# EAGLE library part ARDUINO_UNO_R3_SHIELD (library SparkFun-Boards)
Arduino R3 Shield Footprint Shield form compatible with the Arduino Uno R3. SparkFun Products: MG2639 Cellular Shield MIDI Shield R3 Stackable Headers Kit

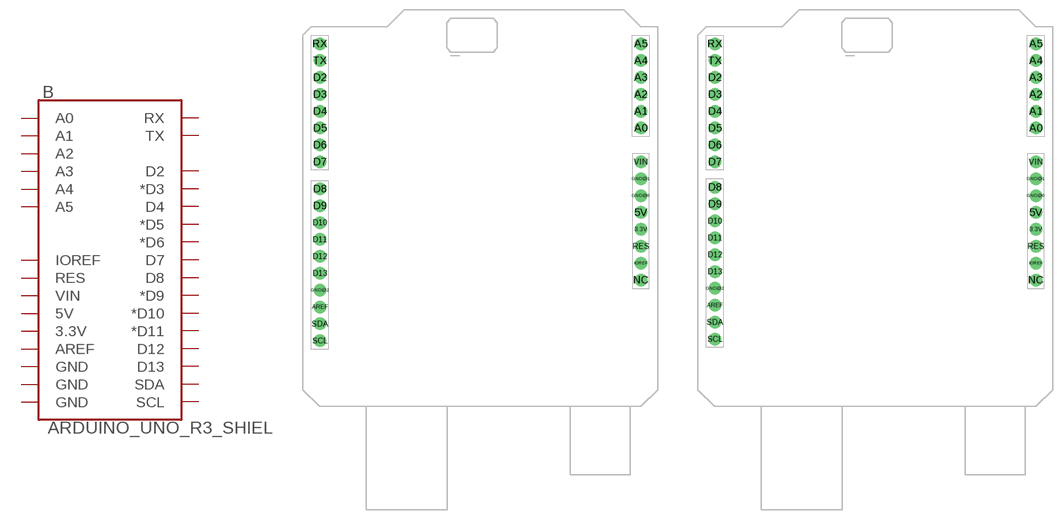
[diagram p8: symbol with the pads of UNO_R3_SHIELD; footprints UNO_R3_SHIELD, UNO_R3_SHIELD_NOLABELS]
Designator prefix B

## ARDUINO_UNO_R3_SHIELDBASIC  [UNO_R3_SHIELD]
3.3V  3.3V
5V  5V
A0  A0
A1  A1
A2  A2
A3  A3
A4  A4
A5  A5
AREF  AREF
D2  D2
D3  *D3
D4  D4
D5  *D5
D6  *D6
D7  D7
D8  D8
D9  *D9
D10  *D10
D11  *D11
D12  D12
D13  D13
GND@0  GND
GND@1  GND
GND@2  GND
IOREF  IOREF
RES  RES
RX  RX
SCL  SCL
SDA  SDA
TX  TX
VIN  VIN

## ARDUINO_UNO_R3_SHIELDNOLABELS  [UNO_R3_SHIELD_NOLABELS]
Pads as for UNO_R3_SHIELD

## ARDUINO_UNO_R3_SHIELDUNO_R3_SHIELD_LOCK  [UNO_R3_SHIELD_LOCK]
Pads as for UNO_R3_SHIELD

## ARDUINO_UNO_R3_SHIELDUNO_R3_SHIELD_NOLABELS_LOCK  [UNO_R3_SHIELD_NOLABELS_LOCK]
Pads as for UNO_R3_SHIELD

## Footprint UNO_R3_SHIELD (pad centres in mm)
Arduino Uno-Compatible Footprint No holes, no ICSP connections. Specifications: Pin count: 32 Pin pitch: 0.1" Area:2.1x2.35" Example device(s): Arduino Uno R3 Shield
drill 1.016 pad 1.88: 3.3V 24.13,-2.54; 5V 24.13,0; A0 24.13,12.7; A1 24.13,15.24; A2 24.13,17.78; A3 24.13,20.32; A4 24.13,22.86; A5 24.13,25.4; AREF -24.13,-14.224; D2 -24.13,20.32; D3 -24.13,17.78; D4 -24.13,15.24; D5 -24.13,12.7; D6 -24.13,10.16; D7 -24.13,7.62; D8 -24.13,3.556; D9 -24.13,1.016; D10 -24.13,-1.524; D11 -24.13,-4.064; D12 -24.13,-6.604; D13 -24.13,-9.144; GND@0 24.13,2.54; GND@1 24.13,5.08; GND@2 -24.13,-11.684; IOREF 24.13,-7.62; NC 24.13,-10.16; RES 24.13,-5.08; RX -24.13,25.4; SCL -24.13,-19.304; SDA -24.13,-16.764; TX -24.13,22.86; VIN 24.13,7.62

## Footprint UNO_R3_SHIELD_NOLABELS (pad centres in mm)
Arduino Uno-Compatible Footprint No holes, no ICSP connections, no silk labels. Specifications: Pin count: 32 Pin pitch: 0.1" Area:2.1x2.35" Example device(s): Arduino Uno R3 Shield
drill 1.016 pad 1.88: 3.3V 24.13,-3.81; 5V 24.13,-1.27; A0 24.13,11.43; A1 24.13,13.97; A2 24.13,16.51; A3 24.13,19.05; A4 24.13,21.59; A5 24.13,24.13; AREF -24.13,-15.24; D2 -24.13,19.05; D3 -24.13,16.51; D4 -24.13,13.97; D5 -24.13,11.43; D6 -24.13,8.89; D7 -24.13,6.35; D8 -24.13,2.54; D9 -24.13,0; D10 -24.13,-2.54; D11 -24.13,-5.08; D12 -24.13,-7.62; D13 -24.13,-10.16; GND@0 24.13,1.27; GND@1 24.13,3.81; GND@2 -24.13,-12.7; IOREF 24.13,-8.89; NC 24.13,-11.43; RES 24.13,-6.35; RX -24.13,24.13; SCL -24.13,-20.32; SDA -24.13,-17.78; TX -24.13,21.59; VIN 24.13,6.35

## Footprint UNO_R3_SHIELD_LOCK (pad centres in mm)
Arduino Uno-Compatible Footprint No holes, no ICSP connections. Locking footprint for headers. Specifications: Pin count: 32 Pin pitch: 0.1" Area:2.1x2.35" Example device(s): Arduino Uno R3 Shield
drill 1.016 pad 1.88: 3.3V 24.13,-3.81; 5V 24.384,-1.27; A0 24.384,11.43; A1 24.13,13.97; A2 24.384,16.51; A3 24.13,19.05; A4 24.384,21.59; A5 24.13,24.13; AREF -24.384,-15.494; D2 -24.13,19.05; D3 -24.384,16.51; D4 -24.13,13.97; D5 -24.384,11.43; D6 -24.13,8.89; D7 -24.384,6.35; D8 -24.13,2.286; D9 -24.384,-0.254; D10 -24.13,-2.794; D11 -24.384,-5.334; D12 -24.13,-7.874; D13 -24.384,-10.414; GND@0 24.13,1.27; GND@1 24.384,3.81; GND@2 -24.13,-12.954; IOREF 24.13,-8.89; NC 24.384,-11.43; RES 24.384,-6.35; RX -24.13,24.13; SCL -24.13,-20.574; SDA -24.13,-18.034; TX -24.384,21.59; VIN 24.13,6.35

## Footprint UNO_R3_SHIELD_NOLABELS_LOCK (pad centres in mm)
Arduino Uno-Compatible Footprint No holes, no ICSP connections, no silk labels. Looking footprint for headers. Specifications: Pin count: 32 Pin pitch: 0.1" Area:2.1x2.35" Example device(s): Arduino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
drill 1.016 pad 1.88: 3.3V 24.13,-3.81; 5V 24.384,-1.27; A0 24.384,11.43; A1 24.13,13.97; A2 24.384,16.51; A3 24.13,19.05; A4 24.384,21.59; A5 24.13,24.13; AREF -24.384,-15.494; D2 -24.13,19.05; D3 -24.384,16.51; D4 -24.13,13.97; D5 -24.384,11.43; D6 -24.13,8.89; D7 -24.384,6.35; D8 -24.13,2.286; D9 -24.384,-0.254; D10 -24.13,-2.794; D11 -24.384,-5.334; D12 -24.13,-7.874; D13 -24.384,-10.414; GND@0 24.13,1.27; GND@1 24.384,3.81; GND@2 -24.13,-12.954; IOREF 24.13,-8.89; NC 24.384,-11.43; RES 24.384,-6.35; RX -24.13,24.13; SCL -24.13,-20.574; SDA -24.13,-18.034; TX -24.384,21.59; VIN 24.13,6.35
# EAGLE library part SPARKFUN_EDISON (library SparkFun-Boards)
SparkFun Edison The Intel® Edison is an ultra small computing platform that will change the way you look at embedded electronics. Each Edison packs a huge amount of tech goodies into a tiny package while still providing the same robust strength of your go-to single board computer. Powered by the Intel® Atom™ SoC dual-core CPU and including an integrated WiFi, Bluetooth LE, and a 70-pin connector to attach a veritable slew of shield-like “Blocks” which can be stacked on top of each other. This device includes footprints for the Edison module itself, as well as the basic board outline used for our Edison blocks. SparkFun Products: Intel Edison SparkFun Console Block SparkFun GPIO Block SparkFun Battery Block SparkFun Base Block SparkFun 9DOF Block SparkFun OLED Block SparkFun Dual H-Bridge Block SparkFun microSD Block SparkFun ADC Block SparkFun I2C Block SparkFun Arduino Block SparkFun Power Block SparkFun PWM Block SparkFun Raspberry Pi Block SparkFun UART Block

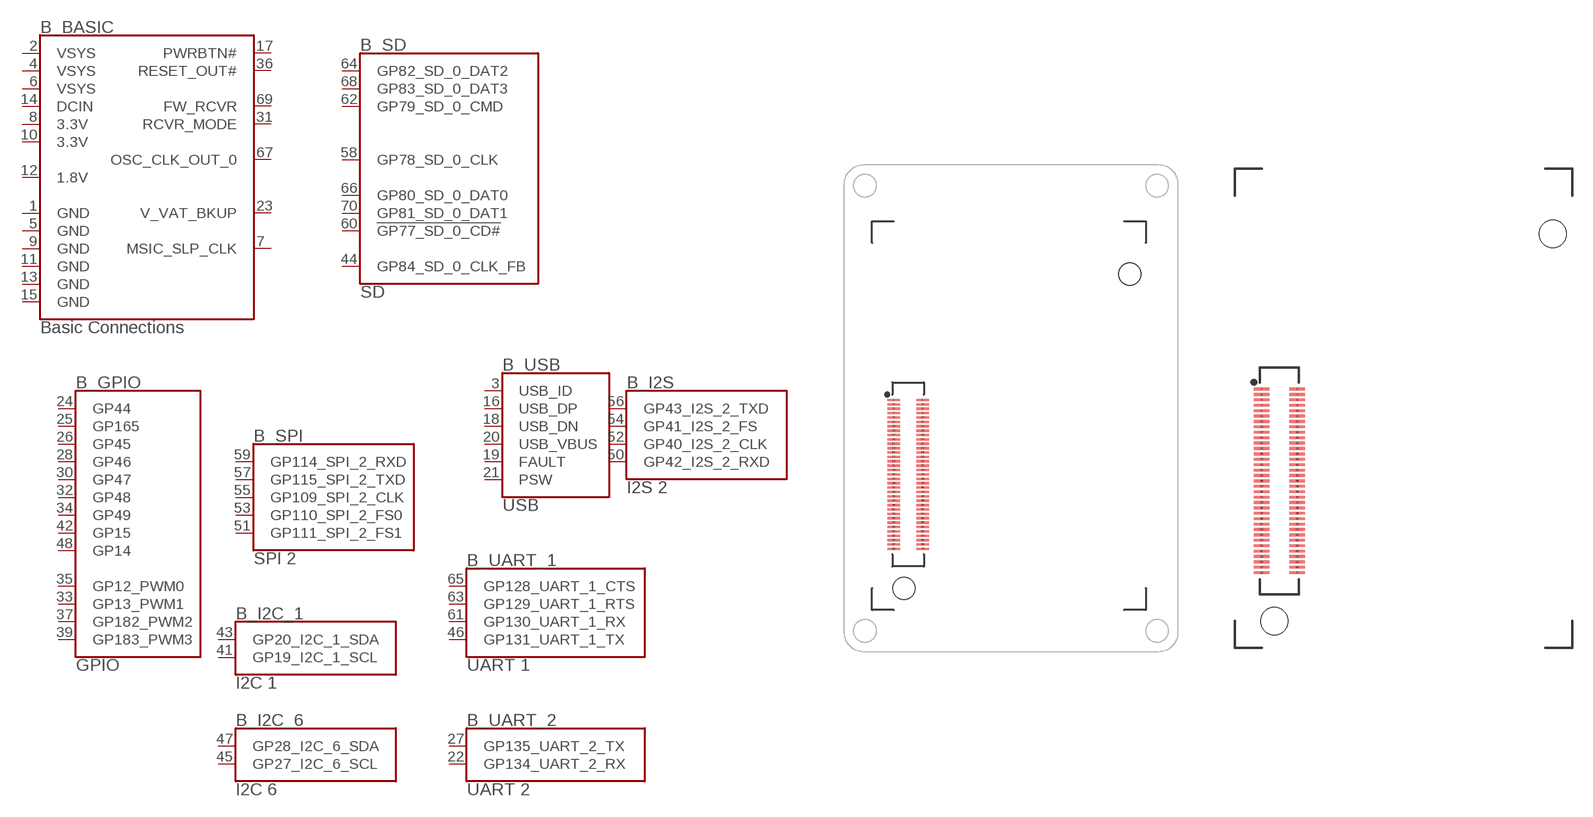
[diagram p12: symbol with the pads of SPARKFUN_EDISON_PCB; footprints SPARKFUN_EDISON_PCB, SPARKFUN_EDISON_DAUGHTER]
Designator prefix B; gates _BASIC=EDISON_CONNECTOR_BASE _GPIO=EDISON_CONNECTOR_GPIO _I2C_1=EDISON_CONNECTOR_I2C_1 _I2C_6=EDISON_CONNECTOR_I2C_6 _I2S=EDISON_CONNECTOR_I2S_2 _SD=EDISON_CONNECTOR_SD _SPI=EDISON_CONNECTOR_SPI_2 _UART_1=EDISON_CONNECTOR_UART_1 _UART_2=EDISON_CONNECTOR_UART_2 _USB=EDISON_CONNECTOR_USB

## SPARKFUN_EDISONPCB  [SPARKFUN_EDISON_PCB]
1  _BASIC:GND  pwr
2  _BASIC:VSYS  pwr
3  _USB:USB_ID
4  _BASIC:VSYS  pwr
5  _BASIC:GND  pwr
6  _BASIC:VSYS  pwr
7  _BASIC:MSIC_SLP_CLK
8  _BASIC:3.3V  pwr
9  _BASIC:GND  pwr
10  _BASIC:3.3V  pwr
11  _BASIC:GND  pwr
12  _BASIC:1.8V  pwr
13  _BASIC:GND  pwr
14  _BASIC:DCIN  pwr
15  _BASIC:GND  pwr
16  _USB:USB_DP
17  _BASIC:PWRBTN#
18  _USB:USB_DN
19  _USB:FAULT
20  _USB:USB_VBUS
21  _USB:PSW
22  _UART_2:GP134_UART_2_RX
23  _BASIC:V_VAT_BKUP  pwr
24  _GPIO:GP44
25  _GPIO:GP165
26  _GPIO:GP45
27  _UART_2:GP135_UART_2_TX
28  _GPIO:GP46
30  _GPIO:GP47
31  _BASIC:RCVR_MODE
32  _GPIO:GP48
33  _GPIO:GP13_PWM1
34  _GPIO:GP49
35  _GPIO:GP12_PWM0
36  _BASIC:RESET_OUT#
37  _GPIO:GP182_PWM2
39  _GPIO:GP183_PWM3
41  _I2C_1:GP19_I2C_1_SCL
42  _GPIO:GP15
43  _I2C_1:GP20_I2C_1_SDA
44  _SD:GP84_SD_0_CLK_FB
45  _I2C_6:GP27_I2C_6_SCL
46  _UART_1:GP131_UART_1_TX
47  _I2C_6:GP28_I2C_6_SDA
48  _GPIO:GP14
50  _I2S:GP42_I2S_2_RXD
51  _SPI:GP111_SPI_2_FS1
52  _I2S:GP40_I2S_2_CLK
53  _SPI:GP110_SPI_2_FS0
54  _I2S:GP41_I2S_2_FS
55  _SPI:GP109_SPI_2_CLK
56  _I2S:GP43_I2S_2_TXD
57  _SPI:GP115_SPI_2_TXD
58  _SD:GP78_SD_0_CLK
59  _SPI:GP114_SPI_2_RXD
60  _SD:!GP77_SD_0_CD#
61  _UART_1:GP130_UART_1_RX
62  _SD:GP79_SD_0_CMD
63  _UART_1:GP129_UART_1_RTS
64  _SD:GP82_SD_0_DAT2
65  _UART_1:GP128_UART_1_CTS
66  _SD:GP80_SD_0_DAT0
67  _BASIC:OSC_CLK_OUT_0
68  _SD:GP83_SD_0_DAT3
69  _BASIC:FW_RCVR
70  _SD:GP81_SD_0_DAT1

## SPARKFUN_EDISON  [SPARKFUN_EDISON_DAUGHTER]
Pads as for SPARKFUN_EDISON_PCB

## Footprint SPARKFUN_EDISON_PCB (pad centres in mm)
SparkFun Edison PCB Footprint for Edison PCBs (view that mates with Edison SBC). Specifications: Pin count:11 Area:1.20 x 1.75 inch Example device(s): SparkFun Edison
smd 1.14 x 0.2: 1 -10.72,1.39; 2 -8.08,1.39; 3 -10.72,0.99; 4 -8.08,0.99; 5 -10.72,0.59; 6 -8.08,0.59; 7 -10.72,0.19; 8 -8.08,0.19; 9 -10.72,-0.21; 10 -8.08,-0.21; 11 -10.72,-0.61; 12 -8.08,-0.61; 13 -10.72,-1.01; 14 -8.08,-1.01; 15 -10.72,-1.41; 16 -8.08,-1.41; 17 -10.72,-1.81; 18 -8.08,-1.81; 19 -10.72,-2.21; 20 -8.08,-2.21; 21 -10.72,-2.61; 22 -8.08,-2.61; 23 -10.72,-3.01; 24 -8.08,-3.01; 25 -10.72,-3.41; 26 -8.08,-3.41; 27 -10.72,-3.81; 28 -8.08,-3.81; 29 -10.72,-4.21; 30 -8.08,-4.21; 31 -10.72,-4.61; 32 -8.08,-4.61; 33 -10.72,-5.01; 34 -8.08,-5.01; 35 -10.72,-5.41; 36 -8.08,-5.41; 37 -10.72,-5.81; 38 -8.08,-5.81; 39 -10.72,-6.21; 40 -8.08,-6.21; 41 -10.72,-6.61; 42 -8.08,-6.61; 43 -10.72,-7.01; 44 -8.08,-7.01; 45 -10.72,-7.41; 46 -8.08,-7.41; 47 -10.72,-7.81; 48 -8.08,-7.81; 49 -10.72,-8.21; 50 -8.08,-8.21; 51 -10.72,-8.61; 52 -8.08,-8.61; 53 -10.72,-9.01; 54 -8.08,-9.01; 55 -10.72,-9.41; 56 -8.08,-9.41; 57 -10.72,-9.81; 58 -8.08,-9.81; 59 -10.72,-10.21; 60 -8.08,-10.21; 61 -10.72,-10.61; 62 -8.08,-10.61; 63 -10.72,-11.01; 64 -8.08,-11.01; 65 -10.72,-11.41; 66 -8.08,-11.41; 67 -10.72,-11.81; 68 -8.08,-11.81; 69 -10.72,-12.21; 70 -8.08,-12.21
hole 2 at 10.83,12.89
hole 2 at -9.77,-15.8

## Footprint SPARKFUN_EDISON_DAUGHTER (pad centres in mm)
SparkFun Edison Daughter Footprint for mating with Edison SBC. Specifications: Pin count:11 Area: 0.98 x 1.4 inch Example device(s): SparkFun Edison
smd 1.14 x 0.2: 1 -11.99,1.39; 2 -9.35,1.39; 3 -11.99,0.99; 4 -9.35,0.99; 5 -11.99,0.59; 6 -9.35,0.59; 7 -11.99,0.19; 8 -9.35,0.19; 9 -11.99,-0.21; 10 -9.35,-0.21; 11 -11.99,-0.61; 12 -9.35,-0.61; 13 -11.99,-1.01; 14 -9.35,-1.01; 15 -11.99,-1.41; 16 -9.35,-1.41; 17 -11.99,-1.81; 18 -9.35,-1.81; 19 -11.99,-2.21; 20 -9.35,-2.21; 21 -11.99,-2.61; 22 -9.35,-2.61; 23 -11.99,-3.01; 24 -9.35,-3.01; 25 -11.99,-3.41; 26 -9.35,-3.41; 27 -11.99,-3.81; 28 -9.35,-3.81; 29 -11.99,-4.21; 30 -9.35,-4.21; 31 -11.99,-4.61; 32 -9.35,-4.61; 33 -11.99,-5.01; 34 -9.35,-5.01; 35 -11.99,-5.41; 36 -9.35,-5.41; 37 -11.99,-5.81; 38 -9.35,-5.81; 39 -11.99,-6.21; 40 -9.35,-6.21; 41 -11.99,-6.61; 42 -9.35,-6.61; 43 -11.99,-7.01; 44 -9.35,-7.01; 45 -11.99,-7.41; 46 -9.35,-7.41; 47 -11.99,-7.81; 48 -9.35,-7.81; 49 -11.99,-8.21; 50 -9.35,-8.21; 51 -11.99,-8.61; 52 -9.35,-8.61; 53 -11.99,-9.01; 54 -9.35,-9.01; 55 -11.99,-9.41; 56 -9.35,-9.41; 57 -11.99,-9.81; 58 -9.35,-9.81; 59 -11.99,-10.21; 60 -9.35,-10.21; 61 -11.99,-10.61; 62 -9.35,-10.61; 63 -11.99,-11.01; 64 -9.35,-11.01; 65 -11.99,-11.41; 66 -9.35,-11.41; 67 -11.99,-11.81; 68 -9.35,-11.81; 69 -11.99,-12.21; 70 -9.35,-12.21
hole 2 at 9.56,12.89
hole 2 at -11.04,-15.8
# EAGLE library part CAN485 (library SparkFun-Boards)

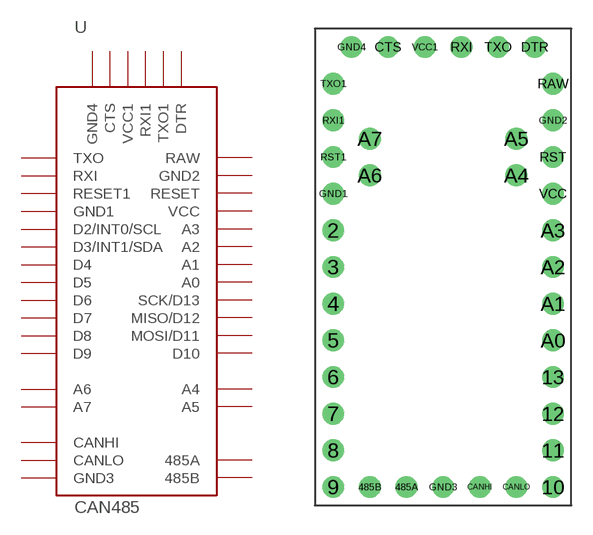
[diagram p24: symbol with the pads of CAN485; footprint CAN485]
Designator prefix -

## CAN485FULL_SOCKET  [CAN485]
2  D2/INT0/SCL
3  D3/INT1/SDA
4  D4
5  D5
6  D6
7  D7
8  D8
9  D9
10  D10
11  MOSI/D11
12  MISO/D12
13  SCK/D13
485A  485A
485B  485B
A0  A0
A1  A1
A2  A2
A3  A3
A4  A4
A5  A5
A6  A6
A7  A7
CANHI  CANHI
CANLO  CANLO
CTS  CTS
DTR  DTR
GND1  GND1
GND2  GND2
GND3  GND3
GND4  GND4
RAW  RAW
RST  RESET
RST1  RESET1
RXI  RXI
RXI1  RXI1
TXO  TXO
TXO1  TXO1
VCC  VCC
VCC1  VCC1

## Footprint CAN485 (pad centres in mm)
drill 1: 2 -7.62,2.54; 3 -7.62,0; 4 -7.62,-2.54; 5 -7.62,-5.08; 6 -7.62,-7.62; 7 -7.62,-10.16; 8 -7.62,-12.7; 9 -7.62,-15.24; 10 7.62,-15.24; 11 7.62,-12.7; 12 7.62,-10.16; 13 7.62,-7.62; 485A -2.54,-15.24; 485B -5.08,-15.24; A0 7.62,-5.08; A1 7.62,-2.54; A2 7.62,0; A3 7.62,2.54; A4 5.08,6.35; A5 5.08,8.89; A6 -5.08,6.35; A7 -5.08,8.89; CANHI 2.54,-15.24; CANLO 5.08,-15.24; CTS -3.81,15.24; DTR 6.35,15.24; GND1 -7.62,5.08; GND2 7.62,10.16; GND3 0,-15.24; GND4 -6.35,15.24; RAW 7.62,12.7; RST 7.62,7.62; RST1 -7.62,7.62; RXI 1.27,15.24; RXI1 -7.62,10.16; TXO 3.81,15.24; TXO1 -7.62,12.7; VCC 7.62,5.08; VCC1 -1.27,15.24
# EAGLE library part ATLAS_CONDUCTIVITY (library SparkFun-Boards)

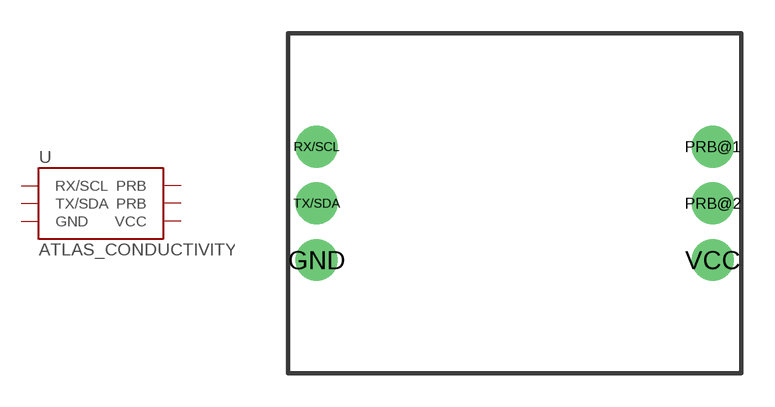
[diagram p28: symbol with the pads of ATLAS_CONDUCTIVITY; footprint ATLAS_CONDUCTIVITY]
Designator prefix U

## ATLAS_CONDUCTIVITY  [ATLAS_CONDUCTIVITY]
GND  GND  pwr
PRB@1  PRB
PRB@2  PRB
RX/SCL  RX/SCL
TX/SDA  TX/SDA
VCC  VCC  pwr

## Footprint ATLAS_CONDUCTIVITY (pad centres in mm)
drill 1.118 pad 1.88: GND 1.27,5.08; PRB@1 19.05,10.16; PRB@2 19.05,7.62; RX/SCL 1.27,10.16; TX/SDA 1.27,7.62; VCC 19.05,5.08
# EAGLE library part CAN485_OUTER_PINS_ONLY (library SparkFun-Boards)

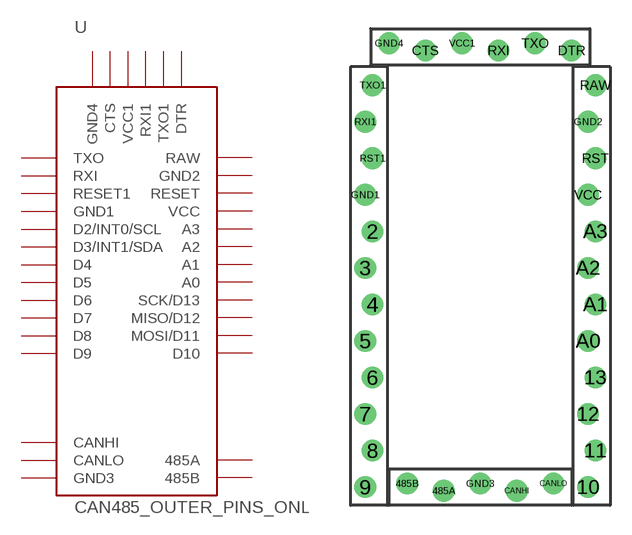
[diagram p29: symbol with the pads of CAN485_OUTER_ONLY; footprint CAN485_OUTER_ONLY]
Designator prefix -

## CAN485_OUTER_PINS_ONLY  [CAN485_OUTER_ONLY]
2  D2/INT0/SCL
3  D3/INT1/SDA
4  D4
5  D5
6  D6
7  D7
8  D8
9  D9
10  D10
11  MOSI/D11
12  MISO/D12
13  SCK/D13
485A  485A
485B  485B
A0  A0
A1  A1
A2  A2
A3  A3
CANHI  CANHI
CANLO  CANLO
CTS  CTS
DTR  DTR
GND1  GND1
GND2  GND2
GND3  GND3
GND4  GND4
RAW  RAW
RST  RESET
RST1  RESET1
RXI  RXI
RXI1  RXI1
TXO  TXO
TXO1  TXO1
VCC  VCC
VCC1  VCC1

## Footprint CAN485_OUTER_ONLY (pad centres in mm)
drill 1: 2 -7.493,0; 3 -8.001,-2.54; 4 -7.493,-5.08; 5 -8.001,-7.62; 6 -7.493,-10.16; 7 -8.001,-12.7; 8 -7.493,-15.24; 9 -8.001,-17.78; 10 7.493,-17.78; 11 8.001,-15.24; 12 7.493,-12.7; 13 8.001,-10.16; 485A -2.54,-18.034; 485B -5.08,-17.526; A0 7.493,-7.62; A1 8.001,-5.08; A2 7.493,-2.54; A3 8.001,0; CANHI 2.54,-18.034; CANLO 5.08,-17.526; CTS -3.81,12.573; DTR 6.35,12.573; GND1 -8.001,2.54; GND2 7.493,7.62; GND3 0,-17.526; GND4 -6.35,13.081; RAW 8.001,10.16; RST 8.001,5.08; RST1 -7.493,5.08; RXI 1.27,12.573; RXI1 -8.001,7.62; TXO 3.81,13.081; TXO1 -7.493,10.16; VCC 7.493,2.54; VCC1 -1.27,13.081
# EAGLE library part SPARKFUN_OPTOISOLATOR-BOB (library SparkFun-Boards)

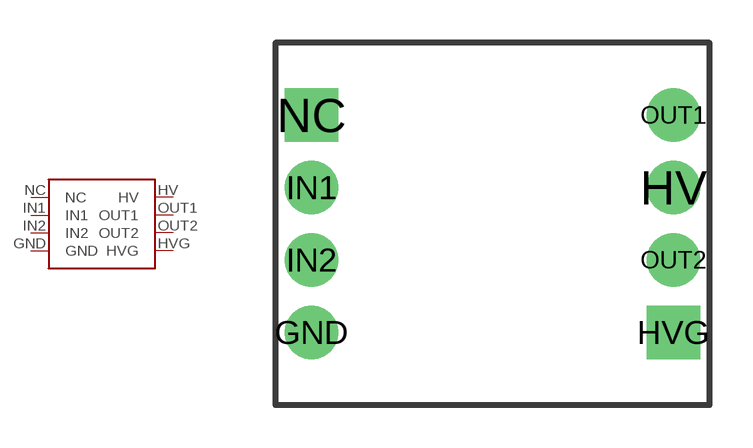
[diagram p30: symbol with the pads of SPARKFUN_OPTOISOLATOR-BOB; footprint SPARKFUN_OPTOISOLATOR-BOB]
Designator prefix -

## SPARKFUN_OPTOISOLATOR-BOB  [SPARKFUN_OPTOISOLATOR-BOB]
GND  GND
HV  HV
HVG  HVG
IN1  IN1
IN2  IN2
NC  NC
OUT1  OUT1
OUT2  OUT2

## Footprint SPARKFUN_OPTOISOLATOR-BOB (pad centres in mm)
drill 1.016 pad 1.88: GND -6.35,-3.81; HV 6.35,1.27; IN1 -6.35,1.27; IN2 -6.35,-1.27; OUT1 6.35,3.81; OUT2 6.35,-1.27
drill 1.016 pad 1.88 square: HVG 6.35,-3.81; NC -6.35,3.81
